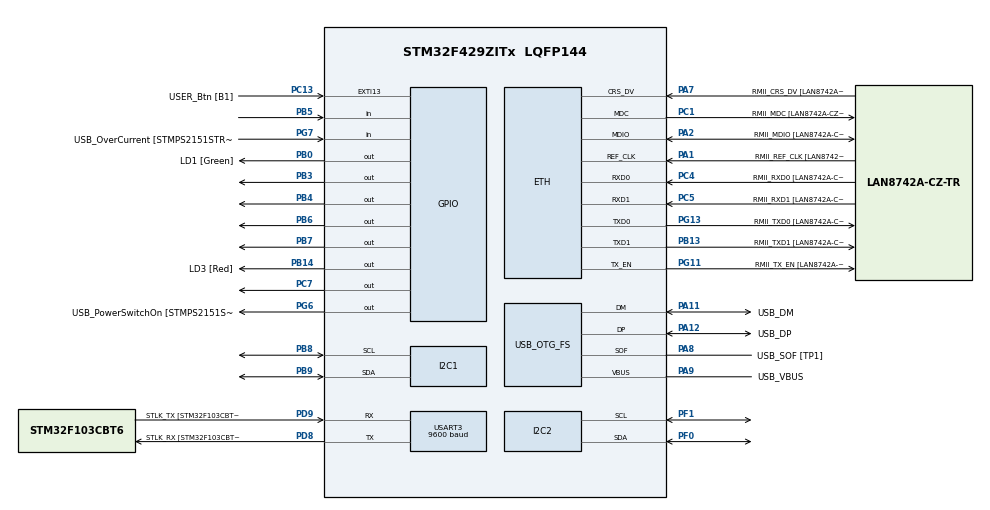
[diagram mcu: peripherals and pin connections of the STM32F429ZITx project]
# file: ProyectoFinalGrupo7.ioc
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ETH.MediaInterface=HAL_ETH_RMII_MODE
ETH.PHY_Name=LAN8742A_PHY_ADDRESS
ETH.PHY_Value=0
ETH.PhyAddress=0
Mcu.Family=STM32F4
Mcu.Name=STM32F429ZITx
Mcu.Package=LQFP144
NVIC.PriorityGroup=NVIC_PRIORITYGROUP_4
PA1.GPIO_Label=RMII_REF_CLK [LAN8742A-CZ-TR_REFCLK0]
PA1.Mode=RMII
PA1.Signal=ETH_REF_CLK
PA10.GPIO_Label=USB_ID
PA10.Signal=USB_OTG_FS_ID
PA11.GPIO_Label=USB_DM
PA11.Mode=Device_Only
PA11.Signal=USB_OTG_FS_DM
PA12.GPIO_Label=USB_DP
PA12.Mode=Device_Only
PA12.Signal=USB_OTG_FS_DP
PA13.GPIO_Label=TMS
PA13.Mode=Serial_Wire
PA13.Signal=SYS_JTMS-SWDIO
PA14.GPIO_Label=TCK
PA14.Mode=Serial_Wire
PA14.Signal=SYS_JTCK-SWCLK
PA2.GPIO_Label=RMII_MDIO [LAN8742A-CZ-TR_MDIO]
PA2.Mode=RMII
PA2.Signal=ETH_MDIO
PA7.GPIO_Label=RMII_CRS_DV [LAN8742A-CZ-TR_CRS_DV]
PA7.Mode=RMII
PA7.Signal=ETH_CRS_DV
PA8.GPIO_Label=USB_SOF [TP1]
PA8.Mode=Activate_SOF_FS
PA8.Signal=USB_OTG_FS_SOF
PA9.GPIO_Label=USB_VBUS
PA9.Mode=Activate_VBUS
PA9.Signal=USB_OTG_FS_VBUS
PB0.GPIO_Label=LD1 [Green]
PB0.Signal=GPIO_Output
PB13.GPIO_Label=RMII_TXD1 [LAN8742A-CZ-TR_TXD1]
PB13.Mode=RMII
PB13.Signal=ETH_TXD1
PB14.GPIO_Label=LD3 [Red]
PB14.Signal=GPIO_Output
PB3.Signal=GPIO_Output
PB4.Signal=GPIO_Output
PB5.Signal=GPIO_Input
PB6.Signal=GPIO_Output
PB7.Signal=GPIO_Output
PB8.Mode=I2C
PB8.Signal=I2C1_SCL
PB9.Mode=I2C
PB9.Signal=I2C1_SDA
PC1.GPIO_Label=RMII_MDC [LAN8742A-CZ-TR_MDC]
PC1.Mode=RMII
PC1.Signal=ETH_MDC
PC13.GPIO_Label=USER_Btn [B1]
PC13.Signal=GPXTI13
PC14/OSC32_IN.Mode=LSE-External-Oscillator
PC14/OSC32_IN.Signal=RCC_OSC32_IN
PC15/OSC32_OUT.Mode=LSE-External-Oscillator
PC15/OSC32_OUT.Signal=RCC_OSC32_OUT
PC4.GPIO_Label=RMII_RXD0 [LAN8742A-CZ-TR_RXD0]
PC4.Mode=RMII
PC4.Signal=ETH_RXD0
PC5.GPIO_Label=RMII_RXD1 [LAN8742A-CZ-TR_RXD1]
PC5.Mode=RMII
PC5.Signal=ETH_RXD1
PC7.Signal=GPIO_Output
PD8.GPIO_Label=STLK_RX [STM32F103CBT6_PA3]
PD8.Mode=Asynchronous
PD8.Signal=USART3_TX
PD9.GPIO_Label=STLK_TX [STM32F103CBT6_PA2]
PD9.Mode=Asynchronous
PD9.Signal=USART3_RX
PF0.Mode=I2C
PF0.Signal=I2C2_SDA
PF1.Mode=I2C
PF1.Signal=I2C2_SCL
PG11.GPIO_Label=RMII_TX_EN [LAN8742A-CZ-TR_TXEN]
PG11.Mode=RMII
PG11.Signal=ETH_TX_EN
PG13.GPIO_Label=RMII_TXD0 [LAN8742A-CZ-TR_TXD0]
PG13.Mode=RMII
PG13.Signal=ETH_TXD0
PG6.GPIO_Label=USB_PowerSwitchOn [STMPS2151STR_EN]
PG6.Signal=GPIO_Output
PG7.GPIO_Label=USB_OverCurrent [STMPS2151STR_FAULT]
PG7.Signal=GPIO_Input
PH0/OSC_IN.GPIO_Label=MCO [STM32F103CBT6_PA8]
PH0/OSC_IN.Mode=HSE-External-Clock-Source
PH0/OSC_IN.Signal=RCC_OSC_IN
PH1/OSC_OUT.Mode=HSE-External-Clock-Source
PH1/OSC_OUT.Signal=RCC_OSC_OUT
ProjectManager.HeapSize=0x200
ProjectManager.StackSize=0x400
ProjectManager.TargetToolchain=STM32CubeIDE
RCC.48MHZClocksFreq_Value=48000000
RCC.AHBFreq_Value=72000000
RCC.APB1CLKDivider=RCC_HCLK_DIV2
RCC.APB1Freq_Value=36000000
RCC.APB1TimFreq_Value=72000000
RCC.APB2CLKDivider=RCC_HCLK_DIV2
RCC.APB2Freq_Value=36000000
RCC.APB2TimFreq_Value=72000000
RCC.CortexFreq_Value=72000000
RCC.HCLKFreq_Value=72000000
RCC.HSE_VALUE=8000000
RCC.HSI_VALUE=16000000
RCC.PLLM=4
RCC.PLLMUL=RCC_PLL_MUL9
RCC.PLLN=72
RCC.PLLQ=3
RCC.PRESCALERUSB=RCC_USBCLKSOURCE_PLL_DIV1_5
RCC.SYSCLKFreq_VALUE=72000000
RCC.SYSCLKSource=RCC_SYSCLKSOURCE_PLLCLK
RCC.SYSCLKSourceVirtual=RCC_SYSCLKSOURCE_PLLCLK
RCC.USBFreq_Value=48000000
RCC.VCOOutputFreq_Value=144000000
USART3.BaudRate=9600
USART3.VirtualMode=VM_ASYNC
USB_OTG_FS.VirtualMode=Device_Only
board=NUCLEO-F429ZI

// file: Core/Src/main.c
/* USER CODE BEGIN Header */
/**
  **********
  * @file           : main.c
  * @brief          : Main program body
  **********
  * @attention
  *
  * Copyright (c) 2023 STMicroelectronics.
  * All rights reserved.
  *
  * This software is licensed under terms that can be found in the LICENSE file
  * in the root directory of this software component.
  * If no LICENSE file comes with this software, it is provided AS-IS.
  *
  **********
  */
/* USER CODE END Header */
#include "main.h"
#include "eth.h"
#include "i2c.h"
#include "usart.h"
#include "usb_otg.h"
#include "gpio.h"
/* USER CODE BEGIN Includes */
#include "API_DHT11_LIB.h"                 //agregado por Sensor de Temperatura y Humedad DHT11
#include "API_uart.h"
#include "stdio.h"                         //agregado por bluetooth HC-05
#include "string.h"                        //agregado por bluetooth HC-05
#include "API_liquidcrystal_i2c.h"         //agregados por lcd

#define DEVICE_ADDR    (0x27 << 1)  // Dirección del LCD (ajustar según tu módulo)

/* USER CODE END Includes */

/* USER CODE BEGIN PV */
char texto[100];
char texto2[16];
char texto3[16];
unsigned int DHT11_TEMP;    // Declarar en al main
unsigned int DHT11_HUM;     //declarar en el main

/* USER CODE END PV */

void SystemClock_Config(void);
/* USER CODE BEGIN PFP */
void MX_USART3_UART_Init(void);
void MX_USB_OTG_FS_PCD_Init(void);
void encenderSoloUnLED(GPIO_TypeDef *port, uint16_t pin);   //FUNCION PARA ACTIVAR LED

uint8_t estadoErrorDHT11 = 0; // Bandera para indicar si hay error con el sensor
/* USER CODE END PFP */

int main(void)
{

	//---------------------LCD--------------------------//
    HAL_Init();
    SystemClock_Config();
    MX_GPIO_Init();
    MX_I2C1_Init();

    // Inicializar LCD
    HD44780_Init(2);
    HD44780_Clear();
    HD44780_SetCursor(0,0);
    HD44780_PrintStr("PROYECTO FINAL");
    HD44780_SetCursor(0,1);
    HD44780_PrintStr("GRUPO N7");

    // Enciende LED Verde (PC7) y apaga los demás
        encenderSoloUnLED(GPIOC, GPIO_PIN_7);

        HAL_Delay(3000);

  /* USER CODE END 1 */

  /* MCU Configuration--------------------------------------------------------*/

  /* Reset of all peripherals, Initializes the Flash interface and the Systick. */
  HAL_Init();

  /* Configure the system clock */
  SystemClock_Config();

  /* Initialize all configured peripherals */
  MX_GPIO_Init();
  MX_I2C1_Init();
  MX_ETH_Init();
  MX_I2C2_Init();
  MX_USART3_UART_Init();
  MX_USB_OTG_FS_PCD_Init();
  /* USER CODE BEGIN 2 */
  delay_us_dwt_init();

  /* USER CODE END 2 */

  /* Infinite loop */
  /* USER CODE BEGIN WHILE */

  // Función para encender solo un LED y apagar los demás

  int error_DHT11 = 0; // Variable para indicar si hay error en el DHT11

  // Bucle principal
  while (1)
     {
         if (error_DHT11) {
             HD44780_Clear();
             HD44780_SetCursor(0, 0);
             HD44780_PrintStr("Error DHT11");

             //Enciende todos los LEDs
             encenderSoloUnLED(GPIOB, GPIO_PIN_3);  // LED AMARILLO ON
             encenderSoloUnLED(GPIOB, GPIO_PIN_4);  // LED VERDE ON
             encenderSoloUnLED(GPIOC, GPIO_PIN_7);  // LED ROJO ON

             //Envia mensaje por Bluetooth
             HAL_UART_Transmit(&huart3, (uint8_t*)"Error DHT11", strlen("Error DHT11"), HAL_MAX_DELAY);
             HAL_UART_Transmit(&huart3, (uint8_t*)"\r\n", 2, HAL_MAX_DELAY);

             HAL_Delay(1000);
             continue;
         }

         if (HAL_GPIO_ReadPin(GPIOB, GPIO_PIN_5) != GPIO_PIN_RESET) {
             HD44780_Clear();
             HD44780_SetCursor(0, 0);
             HD44780_PrintStr("Esperando...");

             //Enciende LED Verde
             encenderSoloUnLED(GPIOB, GPIO_PIN_4);

             //Envia mensaje por Bluetooth
             HAL_UART_Transmit(&huart3, (uint8_t*)"Esperando...", strlen("Esperando..."), HAL_MAX_DELAY);
             HAL_UART_Transmit(&huart3, (uint8_t*)"\r\n", 2, HAL_MAX_DELAY);

         } else {
             if (DHT11_ok() == 1) {
                 error_DHT11 = 0;
                 DHT11_Read();

                 sprintf(texto3, "Temp=%uC", (unsigned int)DHT11_TEMP);
                 sprintf(texto2, "Hum=%u%%", (unsigned int)DHT11_HUM);

                 // Combina temperatura y humedad en una sola línea
                            char mensaje_combinado[32];
                            snprintf(mensaje_combinado, sizeof(mensaje_combinado), "%s %s", texto3, texto2);

                 // Mostrar en LCD
                 HD44780_Clear();
                 HD44780_SetCursor(0, 0);
                 HD44780_PrintStr(texto3);
                 HD44780_SetCursor(0, 1);
                 HD44780_PrintStr(texto2);

                 // Enviar datos combinados por Bluetooth utilizando USART3
                         HAL_UART_Transmit(&huart3, (uint8_t*)mensaje_combinado, strlen(mensaje_combinado), HAL_MAX_DELAY);
                         HAL_UART_Transmit(&huart3, (uint8_t*)"\r\n", 2, HAL_MAX_DELAY);

                 encenderSoloUnLED(GPIOB, GPIO_PIN_3);  // Enciende LED Amarillo
             } else {
                 HD44780_Clear();
                 HD44780_SetCursor(0, 0);
                 HD44780_PrintStr("Error DHT11");

                 //Enciende todos los LEDs
                 encenderSoloUnLED(GPIOB, GPIO_PIN_3);  // LED Amarillo
                 encenderSoloUnLED(GPIOB, GPIO_PIN_4);  // LED VERDE ON
                 encenderSoloUnLED(GPIOC, GPIO_PIN_7);  // LED ROJO ON

                 //Enviar mensaje por Bluetooth
                 HAL_UART_Transmit(&huart3, (uint8_t*)"Error DHT11", strlen("Error DHT11"), HAL_MAX_DELAY);
                 HAL_UART_Transmit(&huart3, (uint8_t*)"\r\n", 2, HAL_MAX_DELAY);

                 error_DHT11 = 1;
             }
         }
         HAL_Delay(1000);  // Esperar antes de la siguiente lectura
     }
}

  void encenderSoloUnLED(GPIO_TypeDef *port, uint16_t pin) {
      HAL_GPIO_WritePin(GPIOC, GPIO_PIN_7, GPIO_PIN_RESET);  // LED ROJO OFF
      HAL_GPIO_WritePin(GPIOB, GPIO_PIN_4, GPIO_PIN_RESET);  // LED VERDE OFF
      HAL_GPIO_WritePin(GPIOB, GPIO_PIN_3, GPIO_PIN_RESET);  // LED Amarillo OFF
      HAL_GPIO_WritePin(port, pin, GPIO_PIN_SET);  // Enciende el LED seleccionado
  }

void SystemClock_Config(void)
{
  RCC_OscInitTypeDef RCC_OscInitStruct = {0};
  RCC_ClkInitTypeDef RCC_ClkInitStruct = {0};

  /** Configure the main internal regulator output voltage
  */
  __HAL_RCC_PWR_CLK_ENABLE();
  __HAL_PWR_VOLTAGESCALING_CONFIG(PWR_REGULATOR_VOLTAGE_SCALE3);

  /** Initializes the RCC Oscillators according to the specified parameters
  * in the RCC_OscInitTypeDef structure.
  */
  RCC_OscInitStruct.OscillatorType = RCC_OSCILLATORTYPE_HSI;
  RCC_OscInitStruct.HSIState = RCC_HSI_ON;
  RCC_OscInitStruct.HSICalibrationValue = RCC_HSICALIBRATION_DEFAULT;
  RCC_OscInitStruct.PLL.PLLState = RCC_PLL_ON;
  RCC_OscInitStruct.PLL.PLLSource = RCC_PLLSOURCE_HSI;
  RCC_OscInitStruct.PLL.PLLM = 16;                     //4
  RCC_OscInitStruct.PLL.PLLN = 192;                    //72
  RCC_OscInitStruct.PLL.PLLP = RCC_PLLP_DIV2;
  RCC_OscInitStruct.PLL.PLLQ = 4;                      //3
  if (HAL_RCC_OscConfig(&RCC_OscInitStruct) != HAL_OK)
  {
    Error_Handler();
  }

  /** Initializes the CPU, AHB and APB buses clocks
  */
  RCC_ClkInitStruct.ClockType = RCC_CLOCKTYPE_HCLK|RCC_CLOCKTYPE_SYSCLK
                              |RCC_CLOCKTYPE_PCLK1|RCC_CLOCKTYPE_PCLK2;
  RCC_ClkInitStruct.SYSCLKSource = RCC_SYSCLKSOURCE_HSI;
  RCC_ClkInitStruct.AHBCLKDivider = RCC_SYSCLK_DIV1;
  RCC_ClkInitStruct.APB1CLKDivider = RCC_HCLK_DIV1;
  RCC_ClkInitStruct.APB2CLKDivider = RCC_HCLK_DIV1;

  if (HAL_RCC_ClockConfig(&RCC_ClkInitStruct, FLASH_LATENCY_0) != HAL_OK)
  {
    Error_Handler();
  }
}

void Error_Handler(void)
{
  __disable_irq();
  while (1)
  {
  }
}
